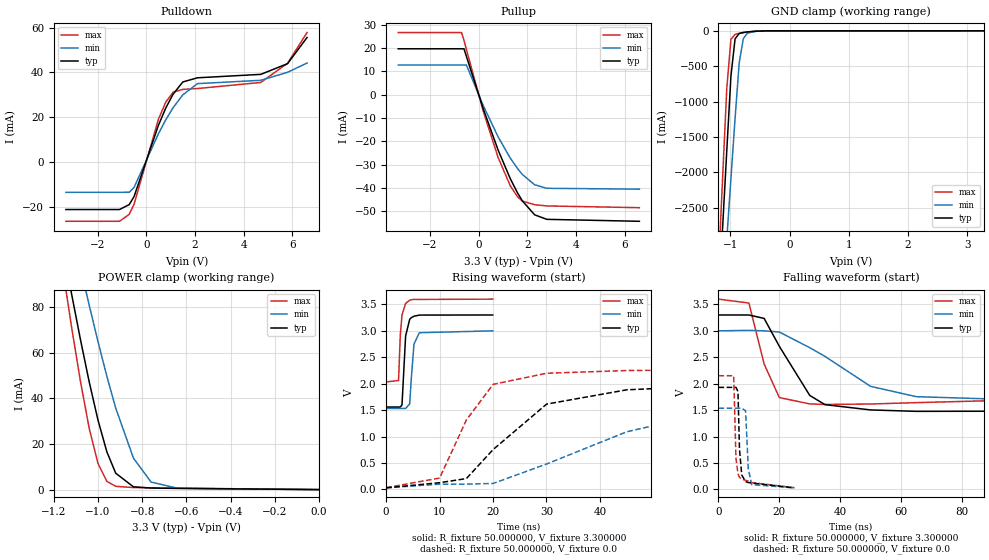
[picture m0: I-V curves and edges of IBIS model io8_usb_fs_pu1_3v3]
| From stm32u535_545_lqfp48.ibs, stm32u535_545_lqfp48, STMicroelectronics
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|   Model io8_usb_fs_pu1_3v3
[Model]  io8_usb_fs_pu1_3v3
Model_type I/O
Polarity   Non-Inverting
Enable   Active-Low
Vinl =   0.990000V
Vinh =   2.310000V
Vmeas =  1.650000V
Cref =   50.000000pF
Rref =   100.000000M
Vref =   0.0V
C_comp   7.156600pF   7.055100pF   7.302500pF
[Temperature Range]   25.000000   0.140000k   -40.000000
[Pullup Reference]   3.300000V   3.000000V   3.600000V
[Pulldown Reference]   0.0V   0.0V   0.0V
[POWER Clamp Reference]   3.300000V   3.000000V   3.600000V
[GND Clamp Reference]   0.0V   0.0V   0.0V
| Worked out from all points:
|   slope of the pulldown table from 0 to 0.495 V, typ, clamps not added: 32.5 ohm
|   slope of the pullup table from 0 to 0.495 V, typ, clamps not added: 32.7 ohm
|   GND clamp passes 1 mA (typ) near -0.45 V on its own axis
|   POWER clamp passes 1 mA (typ) near -0.82 V on its own axis
|   rising waveform, R_fixture 50.000000, V_fixture 3.300000: 20-80 % time 521ps typ, 571ps min, 470ps max; typ from 1.56 V to 3.3 V
|   rising waveform, R_fixture 50.000000, V_fixture 0.0: 20-80 % time 12.3ns typ, 23.1ns min, 6.97ns max; typ from 0.028 V to 1.93 V
|   falling waveform, R_fixture 50.000000, V_fixture 3.300000: 20-80 % time 10.8ns typ, 27.6ns min, 4.17ns max; typ from 3.3 V to 1.56 V
|   falling waveform, R_fixture 50.000000, V_fixture 0.0: 20-80 % time 770ps typ, 733ps min, 701ps max; typ from 1.93 V to 0.028 V
[Pulldown]
|Voltage   I(typ)   I(min)   I(max)
-3.3V     -21.15mA   -13.47mA   -26.4mA
-1.1V     -21.15mA   -13.47mA   -26.4mA
-700mV    -18.95mA   -13.46mA   -23.32mA
-500mV    -15.35mA   -11.27mA   -18.78mA
500mV     16.47mA    12.68mA    19.16mA
800mV     24.11mA    18.88mA    26.75mA
1.1V      30.29mA    24.26mA    31.19mA
1.5V      35.76mA    30.02mA    32.46mA
2.1V      37.62mA    35.02mA    32.83mA
4.7V      39.15mA    36.5mA     35.54mA
5.8V      43.92mA    40.07mA    44.1mA
6.6V      55.6mA     44.2mA     57.8mA
[Pullup]
|Voltage   I(typ)   I(min)   I(max)
-3.3V     19.7mA     12.75mA    26.66mA
-700mV    19.7mA     12.75mA    26.66mA
-600mV    19.7mA     12.75mA    23.38mA
-500mV    16.45mA    12.75mA    19.4mA
200mV     -6.297mA   -4.829mA   -7.346mA
800mV     -23.65mA   -17.98mA   -26.82mA
1.3V      -35.93mA   -27.12mA   -38.99mA
1.6V      -42.06mA   -31.63mA   -43.72mA
1.8V      -45.51mA   -34.16mA   -45.55mA
2.3V      -51.42mA   -38.55mA   -47.08mA
2.8V      -53.36mA   -40.06mA   -47.62mA
6.6V      -54.2mA    -40.43mA   -48.37mA
[GND_clamp]
|Voltage   I(typ)   I(min)   I(max)
-3.3V     -9.287A    -9.833A    -9.745A
-1.2V     -3.857A    -4.664A    -3.345A
-1.13V    -2.774A    -3.805A    -2.072A
-1.06V    -1.695A    -2.947A    -813.1mA
-990mV    -641.8mA   -2.091A    -120.9mA
-920mV    -113.3mA   -1.238A    -49.89mA
-850mV    -36.8mA    -452mA     -36.31mA
-780mV    -22.65mA   -108.9mA   -26.22mA
-710mV    -15.23mA   -32.27mA   -17.43mA
-570mV    -5.119mA   -7.032mA   -4.907mA
-360mV    -90.45uA   -461.6uA   -25.95uA
3.28V     0A         40.32nA    -16.18nA
[POWER_clamp]
|Voltage   I(typ)   I(min)   I(max)
-3.28V    1.357A     1.167A     1.667A
-1.16V    106.8mA    132.5mA    97.01mA
-1.12V    86.01mA    114.9mA    71.53mA
-1.08V    66.05mA    97.65mA    47.75mA
-1.04V    47.29mA    80.94mA    26.91mA
-1V       30.42mA    64.88mA    11.4mA
-960mV    16.55mA    49.71mA    3.613mA
-920mV    7.194mA    35.78mA    1.444mA
-840mV    1.226mA    13.85mA    893.5uA
-760mV    678.5uA    3.311mA    779.5uA
-640mV    531.4uA    582.4uA    631.9uA
0V        0A         50.32nA    0A
[Ramp]
| variable   typ   min   max
dV/dt_r  1.14091/11.97493n   0.90415/23.12904n   1.27310/6.25074n
dV/dt_f  1.04496/10.07051n   0.88164/27.25461n   0.94050/3.78011n
R_load = 50.000000
[Rising Waveform]
R_fixture= 50.000000
V_fixture= 3.300000
V_fixture_min= 3.000000
V_fixture_max= 3.600000
|time   V(typ)   V(min)   V(max)
0s        1.558V     1.531V     2.033V
2.322ns   1.558V     1.531V     2.06V
2.643ns   1.559V     1.531V     2.914V
2.963ns   1.597V     1.531V     3.299V
3.644ns   2.903V     1.53V      3.52V
4.404ns   3.218V     1.618V     3.578V
4.685ns   3.248V     2.071V     3.587V
5.205ns   3.276V     2.748V     3.595V
6.206ns   3.298V     2.964V     3.594V
19.94ns   3.3V       3V         3.6V
[Rising Waveform]
R_fixture= 50.000000
V_fixture= 0.0
V_fixture_min= 0.0
V_fixture_max= 0.0
|time   V(typ)   V(min)   V(max)
0s        28.28mV    27.98mV    31.57mV
10.01ns   125.4mV    98.39mV    213.6mV
15.02ns   204mV      98.42mV    1.314V
20.02ns   753.3mV    110.9mV    1.987V
30.03ns   1.613V     479.6mV    2.197V
45.05ns   1.884V     1.09V      2.249V
55.06ns   1.928V     1.321V     2.255V
70.07ns   1.953V     1.436V     2.256V
140.1ns   1.961V     1.528V     2.249V
2.492us   1.929V     1.535V     2.15V
[Falling Waveform]
R_fixture= 50.000000
V_fixture= 3.300000
V_fixture_min= 3.000000
V_fixture_max= 3.600000
|time   V(typ)   V(min)   V(max)
0s        3.3V       3V         3.6V
10.01ns   3.3V       3.009V     3.526V
15.02ns   3.235V     3V         2.372V
20.02ns   2.707V     2.977V     1.737V
30.03ns   1.777V     2.681V     1.617V
35.04ns   1.603V     2.516V     1.607V
50.05ns   1.503V     1.949V     1.615V
65.07ns   1.476V     1.754V     1.641V
180.2ns   1.486V     1.549V     1.815V
2.492us   1.558V     1.531V     2.033V
[Falling Waveform]
R_fixture= 50.000000
V_fixture= 0.0
V_fixture_min= 0.0
V_fixture_max= 0.0
|time   V(typ)   V(min)   V(max)
0s        1.929V     1.535V     2.15V
5.005ns   1.93V      1.535V     2.15V
5.756ns   1.93V      1.536V     581.6mV
6.406ns   1.851V     1.536V     297.4mV
6.907ns   761.7mV    1.536V     228mV
7.658ns   270.4mV    1.536V     192.6mV
8.909ns   146.6mV    1.487V     170.7mV
9.81ns    129.5mV    386.4mV    157.3mV
10.91ns   120.3mV    89.63mV    128.1mV
24.92ns   28.28mV    27.98mV    31.57mV
